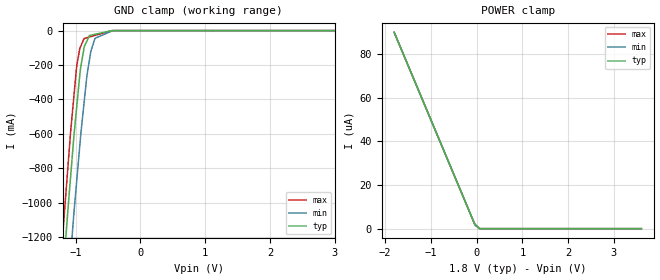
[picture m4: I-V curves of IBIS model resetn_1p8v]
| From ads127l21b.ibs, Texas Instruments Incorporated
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|   resetn_1p8v Model
[Model]   resetn_1p8v
Model_type   Input
Vinl = 0.54
Vinh = 1.26
|   typ   min   max
C_comp   0.6369pF   0.6369pF   0.6369pF
[Voltage Range]   1.8   1.65   1.95
[Temperature Range]   25   125   -40
[Power Clamp Reference]   1.8   1.65   1.95
[GND Clamp Reference]   0   0   0
[GND Clamp]
|   Voltage   I(typ)   I(min)   I(max)
-1.8V     -4.323A    -4.211A    -4.387A
-1.221V   -1.55A     -1.993A    -1.295A
-1.157V   -1.221A    -1.684A    -971.4mA
-1.079V   -849mA     -1.307A    -588.7mA
-1.028V   -613.7mA   -1.061A    -381.1mA
-985.1mV  -445mA     -875.9mA   -209.9mA
-936.5mV  -254.8mA   -666.3mA   -102.9mA
-869.6mV  -96.85mA   -414.1mA   -45.53mA
-766.2mV  -26.95mA   -119.9mA   -34.64mA
-702.3mV  -21.69mA   -45.05mA   -27.9mA
-425.9mV  -241.6uA   -234.4uA   -301.1uA
3.6V      0A         0A         0A
[POWER Clamp]
|   Voltage   I(typ)   I(min)   I(max)
-1.8V     90uA       90uA       90uA
-50.05mV  2.499uA    2.499uA    2.499uA
-28.19mV  1.993uA    1.407uA    1.783uA
57.95mV   0A         233.8nA    182.9nA
3.6V      0A         0A         0A
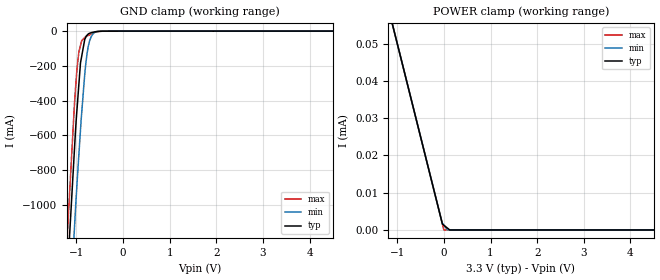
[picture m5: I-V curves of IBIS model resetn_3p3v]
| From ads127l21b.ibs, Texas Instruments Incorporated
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|   resetn_3p3v Model
[Model]   resetn_3p3v
Model_type   Input
Vinl = 0.99
Vinh = 2.31
|   typ   min   max
C_comp   0.6369pF   0.6369pF   0.6369pF
[Voltage Range]   3.3   3   3.6
[Temperature Range]   25   125   -40
[Power Clamp Reference]   3.3   3   3.6
[GND Clamp Reference]   0   0   0
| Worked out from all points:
|   GND clamp passes 1 mA (typ) near -0.49 V on its own axis
[GND Clamp]
|   Voltage   I(typ)   I(min)   I(max)
-3.3V     -8.287A    -7.976A    -8.613A
-1.192V   -1.392A    -1.857A    -1.159A
-1.046V   -702.3mA   -1.155A    -442mA
-987.4mV  -450.9mA   -880mA     -217mA
-947.9mV  -309.8mA   -715mA     -120.9mA
-912.8mV  -184mA     -570mA     -83.33mA
-820.4mV  -47.69mA   -245.7mA   -35.9mA
-774.9mV  -24.51mA   -136mA     -28.96mA
-735.7mV  -14.89mA   -77.02mA   -23.98mA
-643.1mV  -6.689mA   -15.3mA    -12.24mA
-541.7mV  -2.119mA   -1.724mA   -3.519mA
6.6V      0A         0A         0A
[POWER Clamp]
|   Voltage   I(typ)   I(min)   I(max)
-3.3V     165uA      165uA      165uA
-2.258V   112.9uA    112.9uA    112.9uA
-821.2mV  41.05uA    41.06uA    41.05uA
-38.03mV  1.896uA    1.897uA    1.896uA
-31.54mV  1.571uA    1.791uA    1.571uA
-521.1uV  1.262uA    1.285uA    19.81nA
78.26mV   477.9nA    0A         7.2nA
126.3mV   0A         0A         0A
6.6V      0A         0A         0A
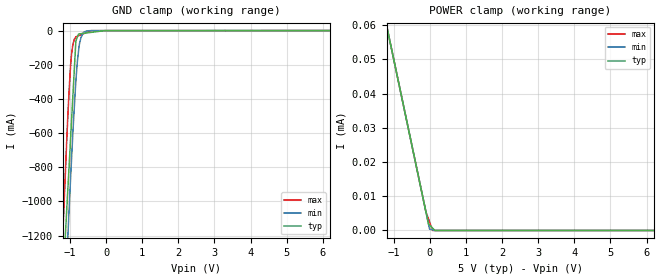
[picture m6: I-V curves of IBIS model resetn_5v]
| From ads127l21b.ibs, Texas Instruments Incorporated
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|   resetn_5v Model
[Model]   resetn_5v
Model_type   Input
Vinl = 1.5
Vinh = 3.5
|   typ   min   max
C_comp   0.6369pF   0.6369pF   0.6369pF
[Voltage Range]   5   4.5   5.5
[Temperature Range]   25   125   -40
[Power Clamp Reference]   5   4.5   5.5
[GND Clamp Reference]   0   0   0
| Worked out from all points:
|   GND clamp passes 1 mA (typ) near -0.06 V on its own axis
[GND Clamp]
|   Voltage   I(typ)   I(min)   I(max)
-5V       -12.75A    -12.24A    -13.3A
-1.196V   -1.463A    -1.853A    -1.172A
-1.093V   -1.058A    -1.359A    -655.1mA
-1.066V   -952.5mA   -1.235A    -527.5mA
-1.031V   -815.9mA   -1.075A    -375.9mA
-980.8mV  -620.7mA   -850.9mA   -197.2mA
-928.9mV  -417.7mA   -633.9mA   -93.18mA
-837.5mV  -60.34mA   -297.3mA   -37.4mA
-761.1mV  -19.87mA   -115.4mA   -29.91mA
-697.8mV  -18.15mA   -42.11mA   -24.45mA
-518.2mV  -13.29mA   -1.213mA   -9.005mA
10V       0A         0A         0A
[POWER Clamp]
|   Voltage   I(typ)   I(min)   I(max)
-5V       250uA      250uA      250uA
-1.23V    61.51uA    61.51uA    61.51uA
-899.1mV  44.94uA    44.95uA    44.94uA
-109.4mV  5.46uA     5.461uA    5.459uA
-37.12mV  1.847uA    1.849uA    3.356uA
-8.821mV  1.553uA    433.9nA    2.532uA
78.14mV   647nA      169.9nA    0A
140.3mV   0A         0A         0A
10V       0A         0A         0A
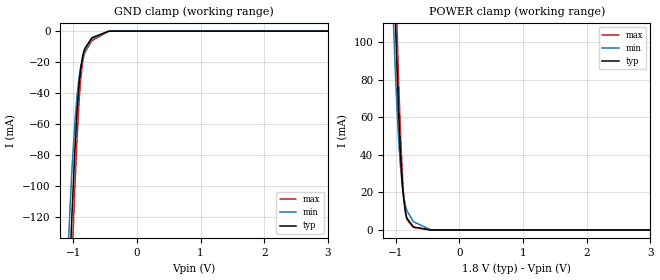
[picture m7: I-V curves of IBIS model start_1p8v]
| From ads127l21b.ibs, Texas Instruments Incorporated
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|   start_1p8v Model
[Model]   start_1p8v
Model_type   Input
Vinl = 0.54
Vinh = 1.26
|   typ   min   max
C_comp   1.6pF   1.6pF   1.6pF
[Voltage Range]   1.8   1.65   1.95
[Temperature Range]   25   125   -40
[Power Clamp Reference]   1.8   1.65   1.95
[GND Clamp Reference]   0   0   0
[GND Clamp]
|   Voltage   I(typ)   I(min)   I(max)
-1.8V     -1.093A    -1.011A    -1.151A
-1.079V   -180.9mA   -140.7mA   -218.2mA
-1.046V   -145.4mA   -111mA     -179.6mA
-1.015V   -114.8mA   -86.6mA    -145.3mA
-970.8mV  -75.08mA   -57.24mA   -98.81mA
-938.9mV  -51.7mA    -41.35mA   -69.33mA
-904.1mV  -32.63mA   -28.91mA   -43.27mA
-881.9mV  -24.1mA    -23.18mA   -31.02mA
-820.2mV  -11.53mA   -13.25mA   -14.14mA
-707.4mV  -4.325mA   -5.115mA   -6.231mA
-388.3mV  -32.02uA   -44.83uA   -35.64uA
3.6V      0A         0A         0A
[POWER Clamp]
|   Voltage   I(typ)   I(min)   I(max)
-1.8V     1.152A     1.085A     1.197A
-1.047V   158.6mA    121.6mA    187.7mA
-1.014V   121.6mA    91.17mA    147.6mA
-1.001V   106.9mA    79.77mA    131.4mA
-955.5mV  63.69mA    48.64mA    81.34mA
-928.6mV  42.93mA    35.1mA     55.15mA
-896.2mV  24.56mA    23.46mA    30mA
-877.4mV  17.25mA    18.64mA    19.6mA
-823.4mV  6.267mA    10.21mA    5.445mA
-720.8mV  1.565mA    4.377mA    1.366mA
-406.8mV  1.385uA    41.54uA    136.4nA
3.6V      0A         0A         0A
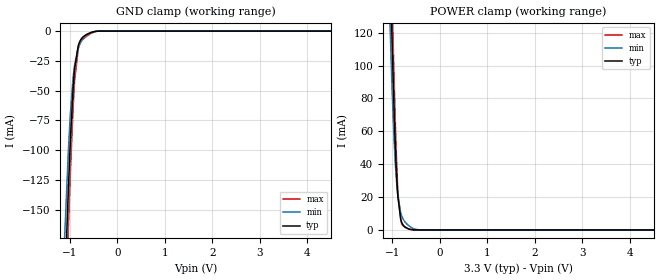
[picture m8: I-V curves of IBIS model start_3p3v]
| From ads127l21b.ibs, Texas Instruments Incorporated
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|   start_3p3v Model
[Model]   start_3p3v
Model_type   Input
Vinl = 0.99
Vinh = 2.31
|   typ   min   max
C_comp   1.6pF   1.6pF   1.6pF
[Voltage Range]   3.3   3   3.6
[Temperature Range]   25   125   -40
[Power Clamp Reference]   3.3   3   3.6
[GND Clamp Reference]   0   0   0
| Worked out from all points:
|   GND clamp passes 1 mA (typ) near -0.54 V on its own axis
|   POWER clamp passes 1 mA (typ) near -0.69 V on its own axis
[GND Clamp]
|   Voltage   I(typ)   I(min)   I(max)
-3.3V     -3.117A    -3.01A     -3.198A
-1.125V   -232.6mA   -185.8mA   -273.2mA
-1.035V   -134.7mA   -102.3mA   -167.8mA
-985.6mV  -87.51mA   -66.1mA    -113.7mA
-937.2mV  -50.59mA   -40.61mA   -67.88mA
-913.8mV  -37.2mA    -31.88mA   -49.73mA
-901.7mV  -31.54mA   -28.19mA   -41.73mA
-824.9mV  -12.11mA   -13.8mA    -14.83mA
-747.1mV  -5.81mA    -7.11mA    -7.861mA
-564.3mV  -1.349mA   -1.236mA   -2.124mA
-387.2mV  -30.85uA   -43.57uA   -34.06uA
6.6V      0A         0A         0A
[POWER Clamp]
|   Voltage   I(typ)   I(min)   I(max)
-3.3V     3.203A     3.129A     3.26A
-1.058V   171mA      132.2mA    200.9mA
-1.032V   141.8mA    107.5mA    169.7mA
-1.003V   109.5mA    81.72mA    134.3mA
-966.5mV  73.47mA    55.32mA    93.07mA
-944.6mV  54.79mA    42.74mA    70.36mA
-921.8mV  38.47mA    32.27mA    49.23mA
-885.4mV  20.1mA     20.55mA    23.64mA
-824.9mV  6.439mA    10.37mA    5.624mA
-684.2mV  984.1uA    3.301mA    839.9uA
-387.2mV  702.2nA    25.42uA    41.75nA
6.6V      0A         0A         0A
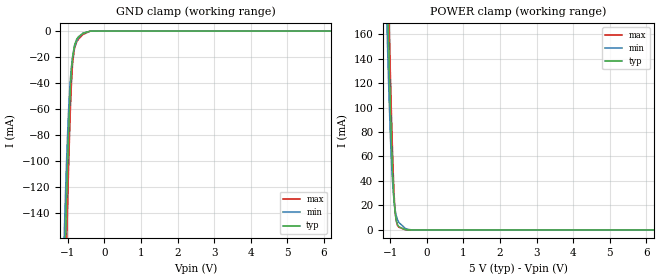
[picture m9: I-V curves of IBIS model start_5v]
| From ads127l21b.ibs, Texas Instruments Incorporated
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|   start_5v Model
[Model]   start_5v
Model_type   Input
Vinl = 1.5
Vinh = 3.5
|   typ   min   max
C_comp   1.6pF   1.6pF   1.6pF
[Voltage Range]   5   4.5   5.5
[Temperature Range]   25   125   -40
[Power Clamp Reference]   5   4.5   5.5
[GND Clamp Reference]   0   0   0
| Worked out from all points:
|   GND clamp passes 1 mA (typ) near -0.50 V on its own axis
|   POWER clamp passes 1 mA (typ) near -0.65 V on its own axis
[GND Clamp]
|   Voltage   I(typ)   I(min)   I(max)
-5V       -5.457A    -5.332A    -5.56A
-1.123V   -230.5mA   -184mA     -271.1mA
-1.09V    -193.2mA   -151.2mA   -231.4mA
-1.055V   -154.6mA   -118.6mA   -189.7mA
-1.029V   -128mA     -96.92mA   -160.2mA
-989.7mV  -91.04mA   -68.66mA   -117.9mA
-939.1mV  -51.76mA   -41.36mA   -69.44mA
-900.4mV  -30.95mA   -27.79mA   -40.9mA
-864mV    -19.06mA   -19.55mA   -23.88mA
-757.6mV  -6.34mA    -7.765mA   -8.42mA
-587.3mV  -1.715mA   -1.639mA   -2.676mA
10V       0A         0A         0A
[POWER Clamp]
|   Voltage   I(typ)   I(min)   I(max)
-5V       5.548A     5.47A      5.617A
-1.09V    210.4mA    166.7mA    242.4mA
-1.057V   170.2mA    131.4mA    200mA
-1.029V   137.7mA    104.2mA    165.2mA
-983.8mV  89.88mA    67.02mA    112.2mA
-939.8mV  51.04mA    40.3mA     65.62mA
-910.9mV  32.03mA    28.21mA    40.47mA
-868.9mV  14.65mA    16.85mA    15.98mA
-838.9mV  8.285mA    12.01mA    7.689mA
-802.6mV  4.464mA    8.373mA    3.712mA
-587.3mV  191.5uA    1.264mA    111.4uA
10V       0A         0A         0A
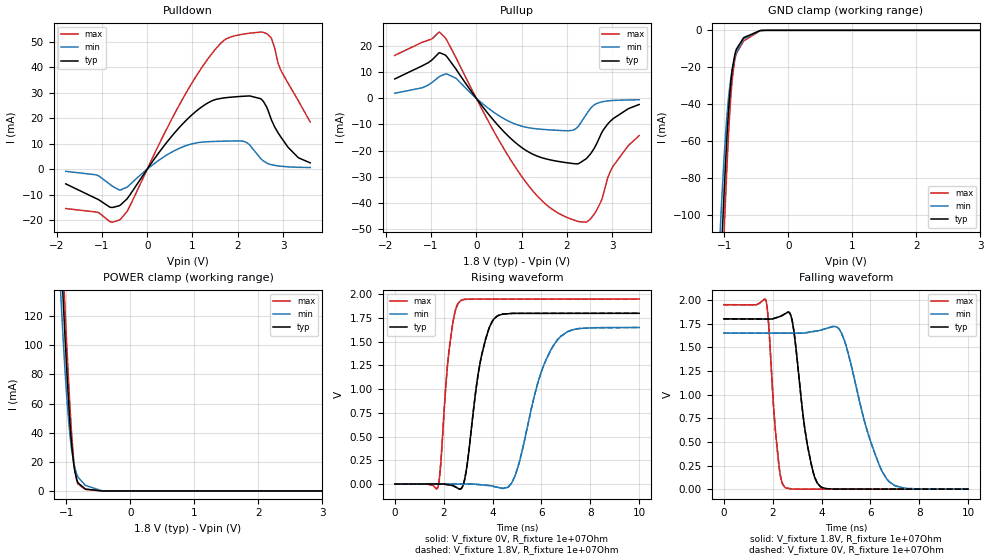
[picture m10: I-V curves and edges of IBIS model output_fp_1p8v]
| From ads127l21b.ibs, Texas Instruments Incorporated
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|   output_fp_1p8v Model
[Model]   output_fp_1p8v
Model_type   3-state
Polarity   Non-Inverting
Vmeas = 0.9
Vref = 0
Cref = 2pF
Rref = 100000
|   typ   min   max
C_comp   1.60pF   1.01pF   1.60pF
[Voltage Range]   1.8   1.65   1.95
[Temperature Range]   25   125   -40
[Pullup Reference]   1.8   1.65   1.95
[Pulldown Reference]   0   -0   0
[Power Clamp Reference]   1.8   1.65   1.95
[GND Clamp Reference]   0   0   0
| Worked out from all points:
|   slope of the pulldown table from 0 to 0.27 V, typ, clamps not added: 39.9 ohm
|   slope of the pullup table from 0 to 0.27 V, typ, clamps not added: 44.6 ohm
|   falling waveform, V_fixture 1.8V, R_fixture 1e+07Ohm: 20-80 % time 530ps typ, 1.05ns min, 321ps max; typ from 1.8 V to 0 V
|   rising waveform, V_fixture 0V, R_fixture 1e+07Ohm: 20-80 % time 595ps typ, 1.02ns min, 373ps max; typ from 0 V to 1.8 V
|   rising waveform, V_fixture 1.8V, R_fixture 1e+07Ohm: 20-80 % time 595ps typ, 1.02ns min, 373ps max; typ from 0 V to 1.8 V
|   falling waveform, V_fixture 0V, R_fixture 1e+07Ohm: 20-80 % time 530ps typ, 1.05ns min, 321ps max; typ from 1.8 V to 0 V
[Pulldown]
|   Voltage   I(typ)   I(min)   I(max)
-1.8V     -5.779mA   -847.1uA   -15.48mA
-1.13V    -11.52mA   -2.235mA   -16.83mA
-817.2mV  -14.97mA   -6.031mA   -20.69mA
-590.4mV  -14.06mA   -8.192mA   -19.64mA
867.6mV   19.31mA    9.288mA    30.22mA
1.445V    26.96mA    10.86mA    45.75mA
1.823V    28.22mA    11.05mA    51.77mA
2.185V    28.68mA    10.55mA    53.2mA
2.509V    27.64mA    4.113mA    53.83mA
2.677V    22.72mA    2.119mA    52.7mA
3.114V    8.527mA    897.9uA    33.69mA
3.6V      2.468mA    648.1uA    18.54mA
[GND Clamp]
|   Voltage   I(typ)   I(min)   I(max)
-1.8V     -864.5mA   -803.3mA   -907.6mA
-1.076V   -146.6mA   -117mA     -174.4mA
-1.039V   -114.9mA   -90.36mA   -140mA
-1.012V   -93.71mA   -73.31mA   -116.3mA
-1.001V   -85.64mA   -67.03mA   -107.1mA
-936mV    -44.28mA   -36.96mA   -57.4mA
-898.2mV  -27.72mA   -25.68mA   -35.42mA
-876.6mV  -21.1mA    -21mA      -26.33mA
-811.8mV  -10.22mA   -11.93mA   -12.55mA
-698.4mV  -3.962mA   -4.625mA   -5.764mA
-385.2mV  -27.8uA    -39.47uA   -29.6uA
3.6V      0A         0A         0A
[Pullup]
|   Voltage   I(typ)   I(min)   I(max)
-1.8V     7.381mA    1.9mA      16.39mA
-806.4mV  17.41mA    8.341mA    25.24mA
-444.6mV  11.07mA    7.621mA    15.4mA
387mV     -8.503mA   -5.364mA   -12.59mA
1.035V    -19.23mA   -10.83mA   -30.65mA
1.597V    -23.44mA   -12.07mA   -41.43mA
2.201V    -25.08mA   -11.62mA   -46.86mA
2.434V    -23.1mA    -6.103mA   -47.42mA
2.596V    -19.46mA   -2.697mA   -44.58mA
2.763V    -13.48mA   -1.427mA   -39.2mA
3.022V    -7.849mA   -844.2uA   -26.04mA
3.6V      -2.384mA   -584.4uA   -14.32mA
[POWER Clamp]
|   Voltage   I(typ)   I(min)   I(max)
-1.8V     906.2mA    854.7mA    940.6mA
-1.098V   176.9mA    144mA      201mA
-1.049V   131.4mA    104mA      153.1mA
-1.017V   102.7mA    80.12mA    122.2mA
-952.2mV  52.48mA    42.27mA    65.03mA
-919.8mV  33.26mA    29.27mA    40.95mA
-887.4mV  19.39mA    20.05mA    22.34mA
-871.2mV  14.49mA    16.65mA    15.66mA
-822.6mV  6.056mA    9.932mA    5.244mA
-703.8mV  1.266mA    3.827mA    1.101mA
-401.4mV  1.156uA    36.32uA    104.9nA
3.6V      0A         0A         0A
[Ramp]
R_load = 1e+07
|   typ   min   max
dV/dt_r   1.08/5.91018e-10   0.989999/1.01383e-09   1.17/3.71034e-10
dV/dt_f   1.08/5.28314e-10   0.99/1.04362e-09   1.17/3.20649e-10
[Falling Waveform]
V_fixture = 1.8V
V_fixture_min = 1.65V
V_fixture_max = 1.95V
R_fixture = 1e+07Ohm
C_fixture = 0F
|   Time   V(typ)   V(min)   V(max)
0s        1.8V       1.65V      1.95V
1.718ns   1.799V     1.649V     2V
2.149ns   1.813V     1.649V     520.4mV
2.493ns   1.852V     1.649V     20.24mV
2.807ns   1.769V     1.649V     2.44mV
3.399ns   497.4mV    1.656V     256.8uV
3.947ns   28.59mV    1.68V      235.9uV
4.818ns   565.3uV    1.649V     202.7uV
6.722ns   360.2uV    91.54mV    130.1uV
10ns      6.947uV    9.111uV    5.152uV
[Rising Waveform]
V_fixture = 0V
V_fixture_min = 0V
V_fixture_max = 0V
R_fixture = 1e+07Ohm
C_fixture = 0F
|   Time   V(typ)   V(min)   V(max)
0s        440.6pV    -3.429uV   454.1pV
1.754ns   131.7uV    123.5uV    -40.93mV
2.224ns   -9.455mV   157.4uV    1.414V
2.671ns   -53.32mV   189.8uV    1.928V
3.52ns    1.316V     -7.709mV   1.95V
4.062ns   1.741V     -26.02mV   1.95V
4.912ns   1.799V     80.42mV    1.95V
5.988ns   1.799V     1.177V     1.95V
6.722ns   1.8V       1.539V     1.95V
10ns      1.8V       1.65V      1.95V
[Rising Waveform]
V_fixture = 1.8V
V_fixture_min = 1.65V
V_fixture_max = 1.95V
R_fixture = 1e+07Ohm
C_fixture = 0F
|   Time   V(typ)   V(min)   V(max)
0s        6.947uV    7.902uV    5.152uV
1.754ns   138.5uV    134.6uV    -40.92mV
2.224ns   -9.447mV   168.5uV    1.414V
2.671ns   -53.31mV   200.8uV    1.928V
3.52ns    1.316V     -7.697mV   1.95V
4.062ns   1.741V     -26mV      1.95V
4.912ns   1.799V     80.47mV    1.95V
5.988ns   1.799V     1.177V     1.95V
6.722ns   1.8V       1.539V     1.95V
10ns      1.8V       1.65V      1.95V
[Falling Waveform]
|Gnd
V_fixture = 0V
V_fixture_min = 0V
V_fixture_max = 0V
R_fixture = 1e+07Ohm
C_fixture = 0F
|   Time   V(typ)   V(min)   V(max)
0s        1.8V       1.65V      1.95V
1.718ns   1.799V     1.649V     2V
2.149ns   1.813V     1.649V     520.4mV
2.493ns   1.852V     1.649V     20.23mV
2.807ns   1.769V     1.649V     2.434mV
3.399ns   497.4mV    1.656V     251.6uV
3.947ns   28.58mV    1.68V      230.8uV
4.818ns   558.3uV    1.649V     197.6uV
6.722ns   353.2uV    91.52mV    125uV
10ns      446.8pV    -2.226uV   454.1pV
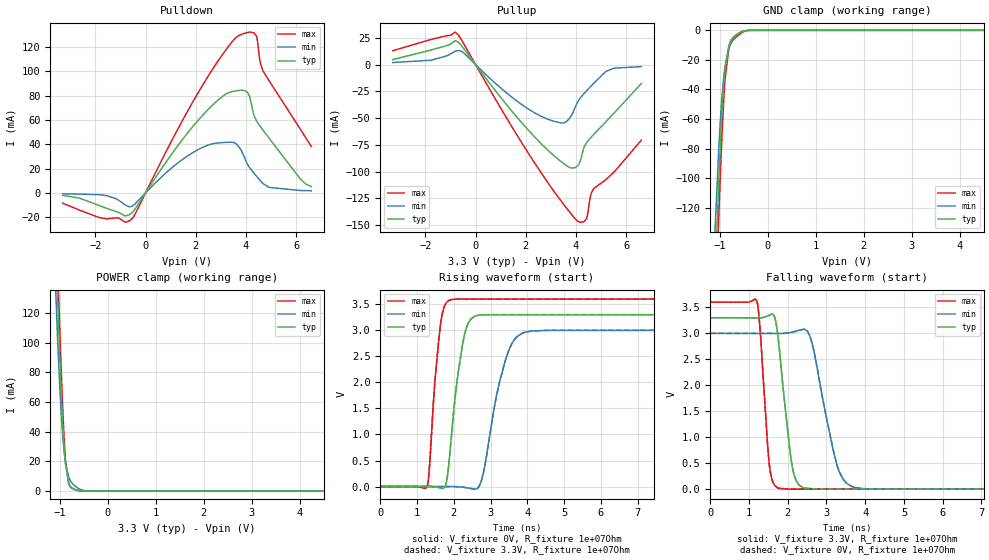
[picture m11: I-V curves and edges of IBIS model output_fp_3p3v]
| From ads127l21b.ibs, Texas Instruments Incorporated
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|   output_fp_3p3v Model
[Model]   output_fp_3p3v
Model_type   3-state
Polarity   Non-Inverting
Vmeas = 1.65
Vref = 0
Cref = 2pF
Rref = 100000
|   typ   min   max
C_comp   1.01pF   1.01pF   1.01pF
[Voltage Range]   3.3   3   3.6
[Temperature Range]   25   125   -40
[Pullup Reference]   3.3   3   3.6
[Pulldown Reference]   -0   0   0
[Power Clamp Reference]   3.3   3   3.6
[GND Clamp Reference]   0   0   0
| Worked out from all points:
|   slope of the pulldown table from 0 to 0.495 V, typ, clamps not added: 31.8 ohm
|   slope of the pullup table from 0 to 0.495 V, typ, clamps not added: 32.1 ohm
|   GND clamp passes 1 mA (typ) near -0.54 V on its own axis
|   POWER clamp passes 1 mA (typ) near -0.69 V on its own axis
|   falling waveform, V_fixture 3.3V, R_fixture 1e+07Ohm: 20-80 % time 279ps typ, 481ps min, 188ps max; typ from 3.3 V to 0 V
|   rising waveform, V_fixture 0V, R_fixture 1e+07Ohm: 20-80 % time 323ps typ, 501ps min, 232ps max; typ from 0 V to 3.3 V
|   rising waveform, V_fixture 3.3V, R_fixture 1e+07Ohm: 20-80 % time 323ps typ, 501ps min, 232ps max; typ from 0 V to 3.3 V
|   falling waveform, V_fixture 0V, R_fixture 1e+07Ohm: 20-80 % time 279ps typ, 481ps min, 188ps max; typ from 3.3 V to 0 V
[Pulldown]
|   Voltage   I(typ)   I(min)   I(max)
-3.3V     -2.063mA   -833.3uA   -8.521mA
-1.845V   -10.48mA   -1.557mA   -20.34mA
-537.9mV  -16.26mA   -11.04mA   -21.18mA
1.234V    37.33mA    23.74mA    50.43mA
2.511V    68.97mA    39.37mA    96.55mA
3.561V    83.66mA    40.92mA    126.9mA
4.046V    82.86mA    23.94mA    131.7mA
4.412V    59.36mA    13.79mA    129.1mA
4.491V    56.79mA    11.87mA    118.7mA
4.561V    54.76mA    10.23mA    107.6mA
4.699V    50.91mA    7.297mA    99.45mA
6.6V      5.109mA    1.688mA    38.09mA
[GND Clamp]
|   Voltage   I(typ)   I(min)   I(max)
-3.3V     -2.449A    -2.37A     -2.507A
-1.112V   -177.9mA   -144.4mA   -207.9mA
-1.092V   -160.4mA   -128.9mA   -189.3mA
-1.023V   -102.5mA   -80.25mA   -126.2mA
-963.6mV  -60.16mA   -48.06mA   -77.17mA
-924mV    -38.31mA   -32.88mA   -49.66mA
-894.3mV  -26.36mA   -24.74mA   -33.56mA
-815.1mV  -10.56mA   -12.26mA   -12.94mA
-795.3mV  -8.686mA   -10.37mA   -10.86mA
-706.2mV  -4.179mA   -4.932mA   -6.025mA
-547.8mV  -1.081mA   -960.5uA   -1.708mA
6.6V      0A         0A         0A
[Pullup]
|   Voltage   I(typ)   I(min)   I(max)
-3.3V     4.684mA    1.989mA    13.02mA
-1.766V   13.74mA    4.181mA    23.57mA
-706.2mV  21.28mA    13.1mA     28.2mA
1.541V    -46.15mA   -32.17mA   -61.74mA
2.858V    -79.51mA   -50.81mA   -109.6mA
3.59V     -93.8mA    -53.7mA    -133.2mA
4.125V    -92.68mA   -32.7mA    -147mA
4.422V    -72.93mA   -24.34mA   -143.6mA
4.571V    -68.67mA   -20.67mA   -123.4mA
4.699V    -65.44mA   -17.56mA   -116.1mA
5.462V    -46.62mA   -3.633mA   -101.6mA
6.6V      -17.63mA   -1.873mA   -70.63mA
[POWER Clamp]
|   Voltage   I(typ)   I(min)   I(max)
-3.3V     2.513A     2.457A     2.555A
-1.102V   180.9mA    147.7mA    205.3mA
-1.053V   134.4mA    106.6mA    156.3mA
-1.033V   116.6mA    91.53mA    137.2mA
-1.003V   91.07mA    70.87mA    109.4mA
-953.7mV  53.51mA    42.98mA    66.26mA
-914.1mV  30.42mA    27.4mA     37.23mA
-884.4mV  18.39mA    19.37mA    20.97mA
-815.1mV  5.352mA    9.246mA    4.542mA
-696.3mV  1.151mA    3.613mA    995.8uA
-399.3mV  1.07uA     34.47uA    87.34nA
6.6V      0A         0A         0A
[Ramp]
R_load = 1e+07
|   typ   min   max
dV/dt_r   1.97999/3.22556e-10   1.79999/5.00327e-10   2.15999/2.31788e-10
dV/dt_f   1.97999/2.79091e-10   1.79999/4.78048e-10   2.15999/1.88288e-10
[Falling Waveform]
V_fixture = 3.3V
V_fixture_min = 3V
V_fixture_max = 3.6V
R_fixture = 1e+07Ohm
C_fixture = 0F
|   Time   V(typ)   V(min)   V(max)
0s        3.3V       3V         3.6V
1.199ns   3.298V     2.999V     3.627V
1.52ns    3.349V     2.998V     502.7mV
1.74ns    2.974V     2.998V     23.52mV
2.105ns   482.3mV    3.022V     225uV
2.396ns   27.88mV    3.077V     217uV
2.667ns   7.32mV     2.689V     209.6uV
3.271ns   353.2uV    464.3mV    193uV
3.652ns   333.8uV    52.22mV    182.6uV
10ns      10.34uV    13.91uV    8.558uV
[Rising Waveform]
V_fixture = 0V
V_fixture_min = 0V
V_fixture_max = 0V
R_fixture = 1e+07Ohm
C_fixture = 0F
|   Time   V(typ)   V(min)   V(max)
0s        972.3pV    30.18nV    658.1pV
1.272ns   704.8uV    382.8uV    -3.481mV
1.625ns   -26.17mV   488.9uV    3.028V
1.858ns   383.1mV    559.3uV    3.57V
2.237ns   2.717V     -11.41mV   3.6V
2.564ns   3.267V     -49.18mV   3.6V
2.817ns   3.296V     291.9mV    3.6V
3.403ns   3.3V       2.417V     3.6V
3.857ns   3.3V       2.942V     3.6V
10ns      3.3V       3V         3.6V
[Rising Waveform]
V_fixture = 3.3V
V_fixture_min = 3V
V_fixture_max = 3.6V
R_fixture = 1e+07Ohm
C_fixture = 0F
|   Time   V(typ)   V(min)   V(max)
0s        10.34uV    13.91uV    8.558uV
1.272ns   715.1uV    396.6uV    -3.469mV
1.625ns   -26.16mV   502.7uV    3.028V
1.858ns   383.1mV    573.1uV    3.57V
2.237ns   2.717V     -11.39mV   3.6V
2.564ns   3.267V     -49.16mV   3.6V
2.817ns   3.296V     291.9mV    3.6V
3.403ns   3.3V       2.417V     3.6V
3.857ns   3.3V       2.942V     3.6V
10ns      3.3V       3V         3.6V
[Falling Waveform]
|Gnd
V_fixture = 0V
V_fixture_min = 0V
V_fixture_max = 0V
R_fixture = 1e+07Ohm
C_fixture = 0F
|   Time   V(typ)   V(min)   V(max)
0s        3.3V       3V         3.6V
1.199ns   3.298V     2.999V     3.627V
1.52ns    3.349V     2.998V     502.6mV
1.74ns    2.974V     2.998V     23.51mV
2.105ns   482.3mV    3.022V     216.4uV
2.396ns   27.87mV    3.077V     208.5uV
2.667ns   7.31mV     2.689V     201uV
3.271ns   342.8uV    464.3mV    184.5uV
3.652ns   323.4uV    52.2mV     174uV
10ns      966.7pV    30.21nV    658.1pV
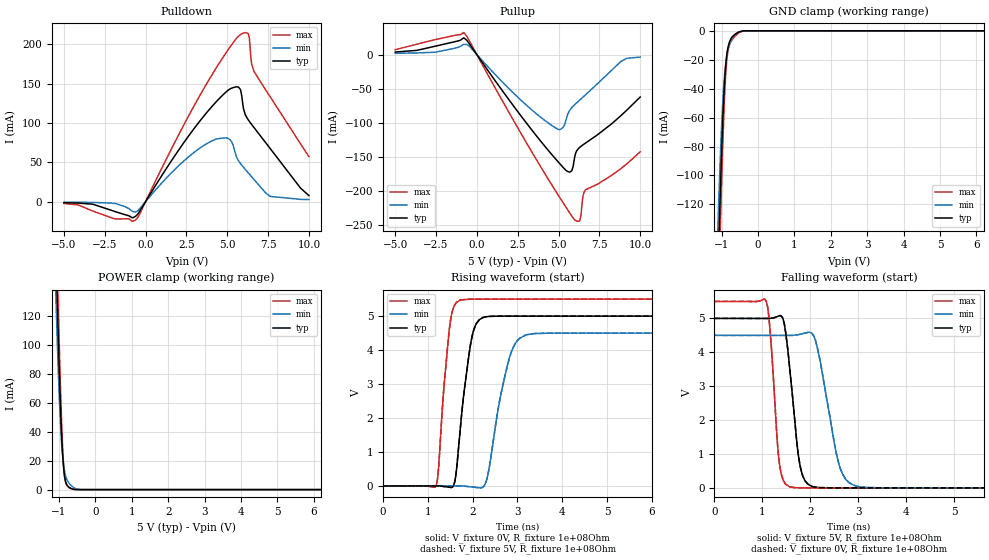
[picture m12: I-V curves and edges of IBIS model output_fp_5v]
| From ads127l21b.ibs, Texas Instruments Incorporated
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|   output_fp_5v Model
[Model]   output_fp_5v
Model_type   3-state
Polarity   Non-Inverting
Vmeas = 2.5
Vref = 0
Cref = 2pF
Rref = 100000
|   typ   min   max
C_comp   1.01pF   0.637pF   1.01pF
[Voltage Range]   5   4.5   5.5
[Temperature Range]   25   125   -40
[Pullup Reference]   5   4.5   5.5
[Pulldown Reference]   0   -0   -0
[Power Clamp Reference]   5   4.5   5.5
[GND Clamp Reference]   0   0   0
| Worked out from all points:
|   slope of the pulldown table from 0 to 0.75 V, typ, clamps not added: 29.8 ohm
|   slope of the pullup table from 0 to 0.75 V, typ, clamps not added: 29.2 ohm
|   GND clamp passes 1 mA (typ) near -0.54 V on its own axis
|   POWER clamp passes 1 mA (typ) near -0.68 V on its own axis
|   falling waveform, V_fixture 5V, R_fixture 1e+08Ohm: 20-80 % time 211ps typ, 338ps min, 152ps max; typ from 5 V to 0 V
|   rising waveform, V_fixture 0V, R_fixture 1e+08Ohm: 20-80 % time 257ps typ, 373ps min, 195ps max; typ from 0 V to 5 V
|   rising waveform, V_fixture 5V, R_fixture 1e+08Ohm: 20-80 % time 257ps typ, 373ps min, 195ps max; typ from 0 V to 5 V
|   falling waveform, V_fixture 0V, R_fixture 1e+08Ohm: 20-80 % time 211ps typ, 338ps min, 152ps max; typ from 5 V to 0 V
[Pulldown]
|   Voltage   I(typ)   I(min)   I(max)
-5V       -1.455mA   -726.9uA   -2.417mA
-620mV    -18.81mA   -13.25mA   -23.41mA
2.23V     71.71mA    49.62mA    93.22mA
4.21V     124.4mA    78.59mA    166.3mA
5.155V    143.2mA    78.95mA    196.2mA
5.68V     145.6mA    52.23mA    210.3mA
6.1V      110.7mA    41.03mA    215mA
6.31V     103.3mA    35.94mA    212.4mA
6.49V     98.21mA    31.61mA    175.4mA
6.64V     94.1mA     28mA       165.5mA
7.63V     67.45mA    6.57mA     133.3mA
10V       7.613mA    2.527mA    57.09mA
[GND Clamp]
|   Voltage   I(typ)   I(min)   I(max)
-5V       -4.274A    -4.183A    -4.346A
-1.13V    -194.1mA   -158.8mA   -225mA
-1.085V   -154mA     -123.3mA   -182.4mA
-1.055V   -128.4mA   -101.5mA   -154.7mA
-1.04V    -116mA     -91.23mA   -141.2mA
-1.025V   -104mA     -81.47mA   -127.9mA
-950mV    -51.93mA   -42.24mA   -67.08mA
-905mV    -30.18mA   -27.36mA   -38.8mA
-860mV    -17.22mA   -18.06mA   -21.12mA
-785mV    -7.876mA   -9.506mA   -9.99mA
-530mV    -855.1uA   -742.7uA   -1.355mA
10V       0A         0A         0A
[Pullup]
|   Voltage   I(typ)   I(min)   I(max)
-5V       3.833mA    1.986mA    7.294mA
-785mV    24.32mA    15.08mA    31.86mA
4.96V     -156.6mA   -109.2mA   -205mA
5.305V    -165.8mA   -105.3mA   -217.9mA
5.695V    -171.9mA   -81.12mA   -232.2mA
5.815V    -169.9mA   -77.5mA    -236.5mA
6.1V      -141.4mA   -70.73mA   -243.7mA
6.31V     -135.4mA   -66.13mA   -242.1mA
6.505V    -131.9mA   -61.91mA   -206.4mA
6.655V    -129.4mA   -58.64mA   -198mA
8.815V    -89.37mA   -10mA      -166.9mA
10V       -62.02mA   -3.53mA    -142.3mA
[POWER Clamp]
|   Voltage   I(typ)   I(min)   I(max)
-5V       4.347A     4.287A     4.396A
-1.085V   164.6mA    133mA      188.2mA
-1.055V   136.6mA    108.4mA    158.6mA
-1.04V    123mA      96.86mA    144.1mA
-1.025V   109.7mA    85.82mA    129.8mA
-950mV    51.06mA    41.29mA    63.31mA
-905mV    26.25mA    24.64mA    31.66mA
-875mV    15.53mA    17.39mA    17.07mA
-815mV    5.343mA    9.238mA    4.533mA
-665mV    750.4uA    2.801mA    618.6uA
-395mV    915.6nA    30.95uA    61.16nA
10V       0A         0A         0A
[Ramp]
R_load = 1e+08
|   typ   min   max
dV/dt_r   3/2.5505e-10   2.7/3.7237e-10   3.3/1.94848e-10
dV/dt_f   3/2.11243e-10   2.7/3.36641e-10   3.3/1.52222e-10
[Falling Waveform]
V_fixture = 5V
V_fixture_min = 4.5V
V_fixture_max = 5.5V
R_fixture = 1e+08Ohm
C_fixture = 0F
|   Time   V(typ)   V(min)   V(max)
0s        5V         4.5V       5.5V
1.086ns   4.999V     4.499V     5.492V
1.354ns   5.075V     4.499V     764.9mV
1.56ns    3.71V      4.499V     37.37mV
1.753ns   965mV      4.521V     4.301mV
1.886ns   224.9mV    4.565V     348.2uV
2.141ns   15.98mV    4.182V     337.3uV
2.623ns   294.6uV    593.6mV    316.7uV
2.927ns   282.5uV    65.39mV    303.7uV
10ns      1.479uV    1.844uV    1.28uV
[Rising Waveform]
V_fixture = 0V
V_fixture_min = 0V
V_fixture_max = 0V
R_fixture = 1e+08Ohm
C_fixture = 0F
|   Time   V(typ)   V(min)   V(max)
0s        1.492nV    29.84nV    3.838nV
1.183ns   949.4uV    672.6uV    9.097mV
1.497ns   -39.51mV   850.6uV    4.782V
1.611ns   198mV      915.8uV    5.349V
1.713ns   1.518V     973.7uV    5.468V
2.085ns   4.786V     -43.83mV   5.5V
2.325ns   4.985V     248.4mV    5.5V
2.829ns   5V         3.807V     5.5V
3.174ns   5V         4.437V     5.5V
10ns      5V         4.5V       5.5V
[Rising Waveform]
V_fixture = 5V
V_fixture_min = 4.5V
V_fixture_max = 5.5V
R_fixture = 1e+08Ohm
C_fixture = 0F
|   Time   V(typ)   V(min)   V(max)
0s        1.479uV    1.844uV    1.28uV
1.183ns   950.8uV    674.4uV    9.102mV
1.497ns   -39.51mV   852.4uV    4.782V
1.611ns   198.1mV    917.6uV    5.349V
1.713ns   1.518V     975.5uV    5.468V
2.085ns   4.786V     -43.83mV   5.5V
2.325ns   4.985V     248.4mV    5.5V
2.829ns   5V         3.807V     5.5V
3.174ns   5V         4.437V     5.5V
10ns      5V         4.5V       5.5V
[Falling Waveform]
|Gnd
V_fixture = 0V
V_fixture_min = 0V
V_fixture_max = 0V
R_fixture = 1e+08Ohm
C_fixture = 0F
|   Time   V(typ)   V(min)   V(max)
0s        5V         4.5V       5.5V
1.086ns   4.999V     4.499V     5.492V
1.354ns   5.075V     4.499V     764.9mV
1.56ns    3.71V      4.499V     37.37mV
1.753ns   965mV      4.521V     4.3mV
1.886ns   224.9mV    4.565V     346.9uV
2.141ns   15.98mV    4.182V     336.1uV
2.623ns   293.1uV    593.6mV    315.4uV
2.927ns   281.1uV    65.39mV    302.4uV
10ns      1.492nV    29.84nV    3.838nV
